// Mitsubishi GX Works2 project: optexfa-cdx_ce_v100a_j   PLC: Q04UDV

PROGRAM MAIN
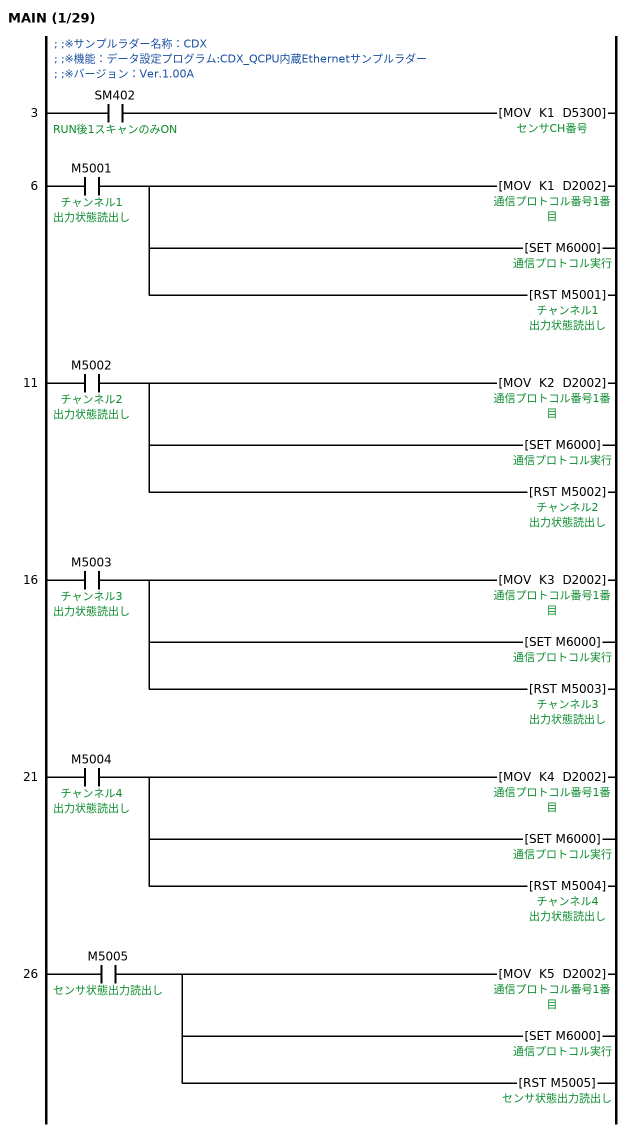
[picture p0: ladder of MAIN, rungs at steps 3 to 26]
; ※サンプルラダー名称：CDX
; ※機能：データ設定プログラム:CDX_QCPU内蔵Ethernetサンプルラダー
; ※バージョン：Ver.1.00A
3     LD      SM402  ; RUN後1スキャンのみON
      MOV     K1 D5300  ; センサCH番号
6     LD      M5001  ; チャンネル1 出力状態読出し
      MOV     K1 D2002  ; 通信プロトコル番号1番目
      SET     M6000  ; 通信プロトコル実行
      RST     M5001  ; チャンネル1 出力状態読出し
11    LD      M5002  ; チャンネル2 出力状態読出し
      MOV     K2 D2002
      SET     M6000  ; 通信プロトコル実行
      RST     M5002  ; チャンネル2 出力状態読出し
16    LD      M5003  ; チャンネル3 出力状態読出し
      MOV     K3 D2002
      SET     M6000  ; 通信プロトコル実行
      RST     M5003  ; チャンネル3 出力状態読出し
21    LD      M5004  ; チャンネル4 出力状態読出し
      MOV     K4 D2002
      SET     M6000  ; 通信プロトコル実行
      RST     M5004  ; チャンネル4 出力状態読出し
26    LD      M5005  ; センサ状態出力読出し
      MOV     K5 D2002
      SET     M6000  ; 通信プロトコル実行
      RST     M5005  ; センサ状態出力読出し
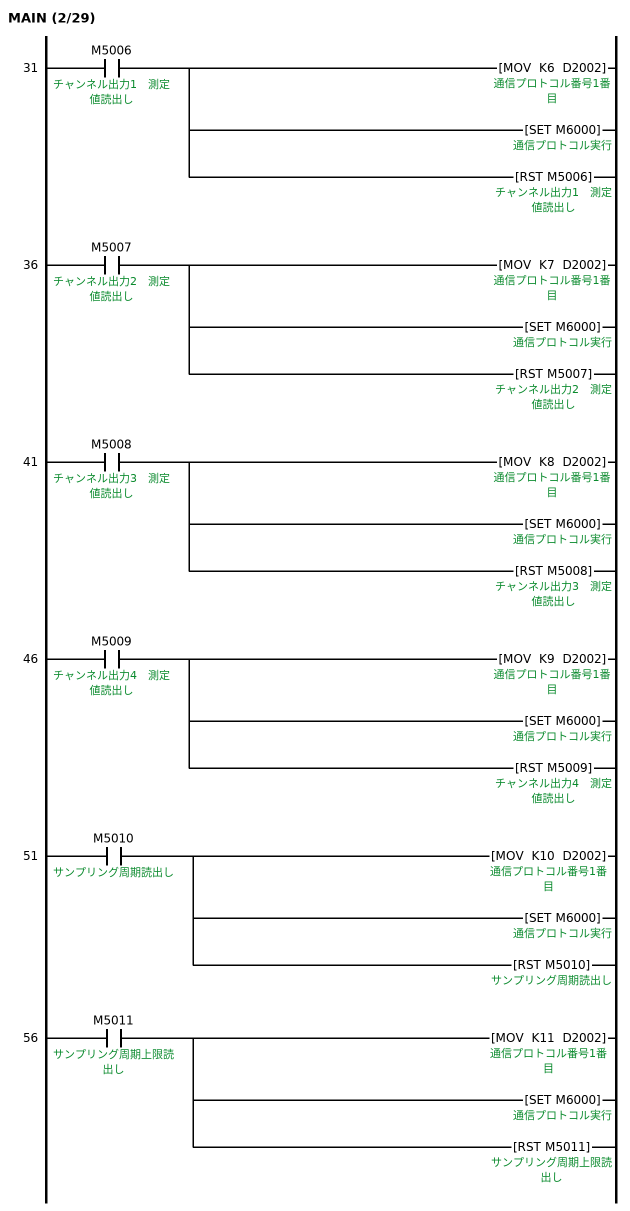
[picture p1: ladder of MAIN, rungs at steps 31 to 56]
31    LD      M5006  ; チャンネル出力1　測定値読出し
      MOV     K6 D2002
      SET     M6000  ; 通信プロトコル実行
      RST     M5006  ; チャンネル出力1　測定値読出し
36    LD      M5007  ; チャンネル出力2　測定値読出し
      MOV     K7 D2002
      SET     M6000  ; 通信プロトコル実行
      RST     M5007  ; チャンネル出力2　測定値読出し
41    LD      M5008  ; チャンネル出力3　測定値読出し
      MOV     K8 D2002
      SET     M6000  ; 通信プロトコル実行
      RST     M5008  ; チャンネル出力3　測定値読出し
46    LD      M5009  ; チャンネル出力4　測定値読出し
      MOV     K9 D2002
      SET     M6000  ; 通信プロトコル実行
      RST     M5009  ; チャンネル出力4　測定値読出し
51    LD      M5010  ; サンプリング周期読出し
      MOV     K10 D2002
      SET     M6000  ; 通信プロトコル実行
      RST     M5010  ; サンプリング周期読出し
56    LD      M5011  ; サンプリング周期上限読出し
      MOV     K11 D2002
      SET     M6000  ; 通信プロトコル実行
      RST     M5011  ; サンプリング周期上限読出し
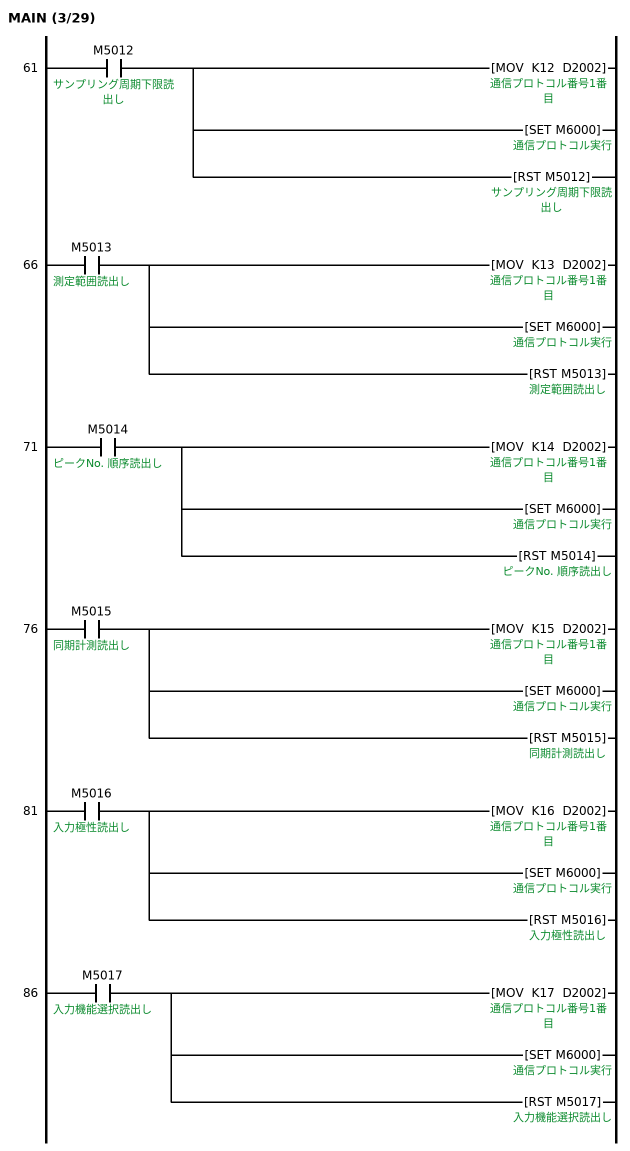
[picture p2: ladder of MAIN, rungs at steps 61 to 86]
61    LD      M5012  ; サンプリング周期下限読出し
      MOV     K12 D2002
      SET     M6000  ; 通信プロトコル実行
      RST     M5012  ; サンプリング周期下限読出し
66    LD      M5013  ; 測定範囲読出し
      MOV     K13 D2002
      SET     M6000  ; 通信プロトコル実行
      RST     M5013  ; 測定範囲読出し
71    LD      M5014  ; ピークNo. 順序読出し
      MOV     K14 D2002
      SET     M6000  ; 通信プロトコル実行
      RST     M5014  ; ピークNo. 順序読出し
76    LD      M5015  ; 同期計測読出し
      MOV     K15 D2002
      SET     M6000  ; 通信プロトコル実行
      RST     M5015  ; 同期計測読出し
81    LD      M5016  ; 入力極性読出し
      MOV     K16 D2002
      SET     M6000  ; 通信プロトコル実行
      RST     M5016  ; 入力極性読出し
86    LD      M5017  ; 入力機能選択読出し
      MOV     K17 D2002
      SET     M6000  ; 通信プロトコル実行
      RST     M5017  ; 入力機能選択読出し
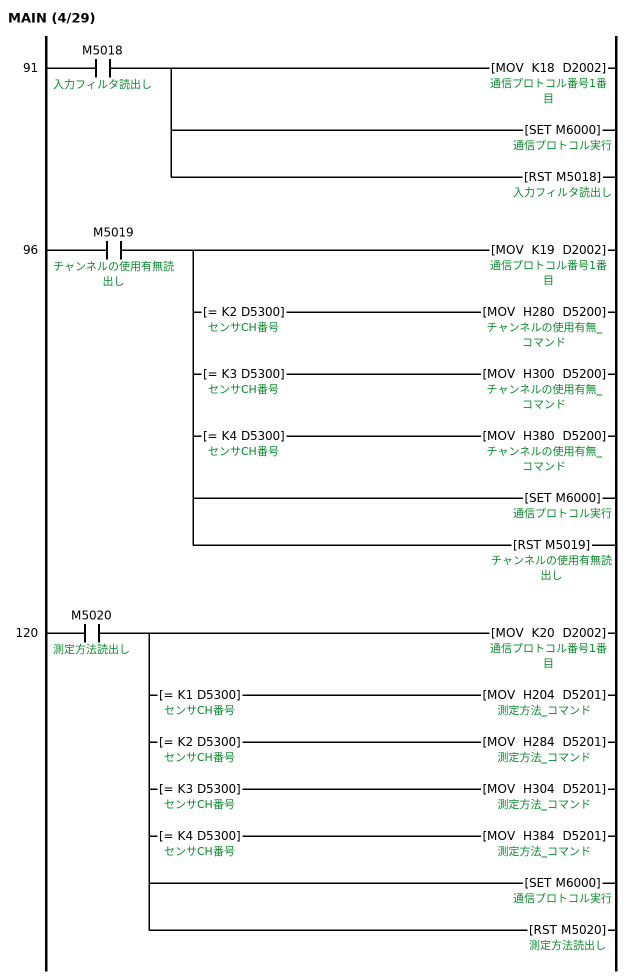
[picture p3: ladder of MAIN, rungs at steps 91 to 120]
91    LD      M5018  ; 入力フィルタ読出し
      MOV     K18 D2002
      SET     M6000  ; 通信プロトコル実行
      RST     M5018  ; 入力フィルタ読出し
96    LD      M5019  ; チャンネルの使用有無読出し
      MOV     K19 D2002
      MPS
      AND=    K2 D5300  ; センサCH番号
      MOV     H280 D5200  ; チャンネルの使用有無_コマンド
      MRD
      AND=    K3 D5300  ; センサCH番号
      MOV     H300 D5200
      MRD
      AND=    K4 D5300  ; センサCH番号
      MOV     H380 D5200
      MPP
      SET     M6000  ; 通信プロトコル実行
      RST     M5019  ; チャンネルの使用有無読出し
120   LD      M5020  ; 測定方法読出し
      MOV     K20 D2002
      MPS
      AND=    K1 D5300  ; センサCH番号
      MOV     H204 D5201  ; 測定方法_コマンド
      MRD
      AND=    K2 D5300  ; センサCH番号
      MOV     H284 D5201
      MRD
      AND=    K3 D5300  ; センサCH番号
      MOV     H304 D5201
      MRD
      AND=    K4 D5300  ; センサCH番号
      MOV     H384 D5201
      MPP
      SET     M6000  ; 通信プロトコル実行
      RST     M5020  ; 測定方法読出し
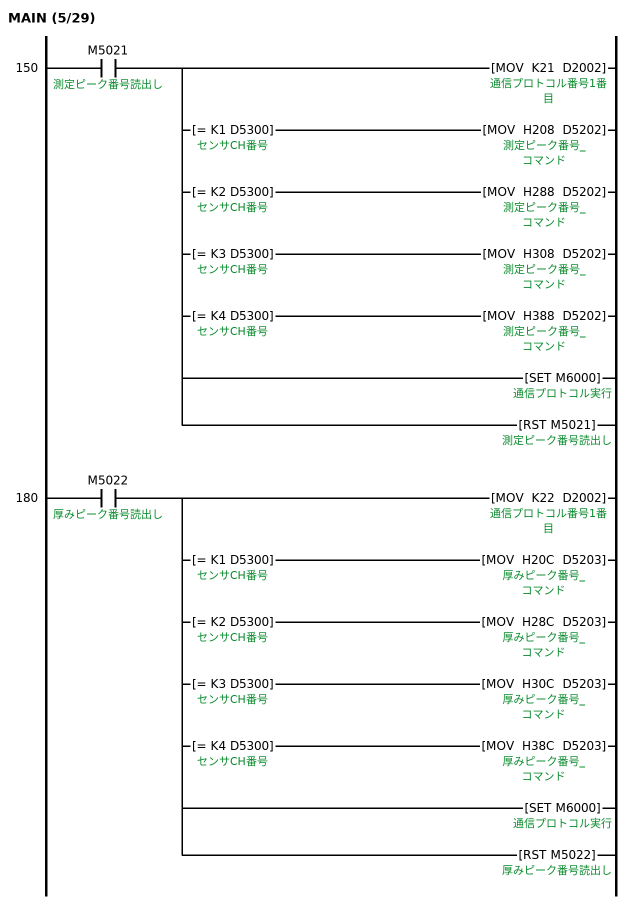
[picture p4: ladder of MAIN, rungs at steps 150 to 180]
150   LD      M5021  ; 測定ピーク番号読出し
      MOV     K21 D2002
      MPS
      AND=    K1 D5300  ; センサCH番号
      MOV     H208 D5202  ; 測定ピーク番号_コマンド
      MRD
      AND=    K2 D5300  ; センサCH番号
      MOV     H288 D5202
      MRD
      AND=    K3 D5300  ; センサCH番号
      MOV     H308 D5202
      MRD
      AND=    K4 D5300  ; センサCH番号
      MOV     H388 D5202
      MPP
      SET     M6000  ; 通信プロトコル実行
      RST     M5021  ; 測定ピーク番号読出し
180   LD      M5022  ; 厚みピーク番号読出し
      MOV     K22 D2002
      MPS
      AND=    K1 D5300  ; センサCH番号
      MOV     H20C D5203  ; 厚みピーク番号_コマンド
      MRD
      AND=    K2 D5300  ; センサCH番号
      MOV     H28C D5203
      MRD
      AND=    K3 D5300  ; センサCH番号
      MOV     H30C D5203
      MRD
      AND=    K4 D5300  ; センサCH番号
      MOV     H38C D5203
      MPP
      SET     M6000  ; 通信プロトコル実行
      RST     M5022  ; 厚みピーク番号読出し
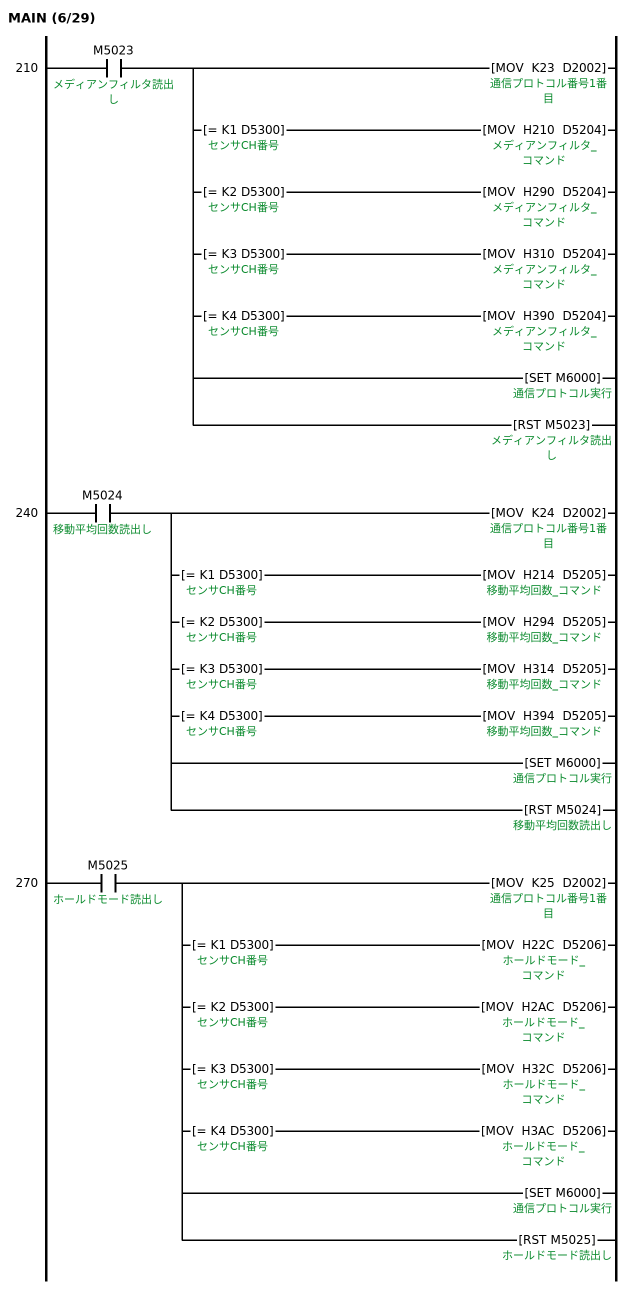
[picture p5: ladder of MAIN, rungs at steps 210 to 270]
210   LD      M5023  ; メディアンフィルタ読出し
      MOV     K23 D2002
      MPS
      AND=    K1 D5300  ; センサCH番号
      MOV     H210 D5204  ; メディアンフィルタ_コマンド
      MRD
      AND=    K2 D5300  ; センサCH番号
      MOV     H290 D5204
      MRD
      AND=    K3 D5300  ; センサCH番号
      MOV     H310 D5204
      MRD
      AND=    K4 D5300  ; センサCH番号
      MOV     H390 D5204
      MPP
      SET     M6000  ; 通信プロトコル実行
      RST     M5023  ; メディアンフィルタ読出し
240   LD      M5024  ; 移動平均回数読出し
      MOV     K24 D2002
      MPS
      AND=    K1 D5300  ; センサCH番号
      MOV     H214 D5205  ; 移動平均回数_コマンド
      MRD
      AND=    K2 D5300  ; センサCH番号
      MOV     H294 D5205
      MRD
      AND=    K3 D5300  ; センサCH番号
      MOV     H314 D5205
      MRD
      AND=    K4 D5300  ; センサCH番号
      MOV     H394 D5205
      MPP
      SET     M6000  ; 通信プロトコル実行
      RST     M5024  ; 移動平均回数読出し
270   LD      M5025  ; ホールドモード読出し
      MOV     K25 D2002
      MPS
      AND=    K1 D5300  ; センサCH番号
      MOV     H22C D5206  ; ホールドモード_コマンド
      MRD
      AND=    K2 D5300  ; センサCH番号
      MOV     H2AC D5206
      MRD
      AND=    K3 D5300  ; センサCH番号
      MOV     H32C D5206
      MRD
      AND=    K4 D5300  ; センサCH番号
      MOV     H3AC D5206
      MPP
      SET     M6000  ; 通信プロトコル実行
      RST     M5025  ; ホールドモード読出し
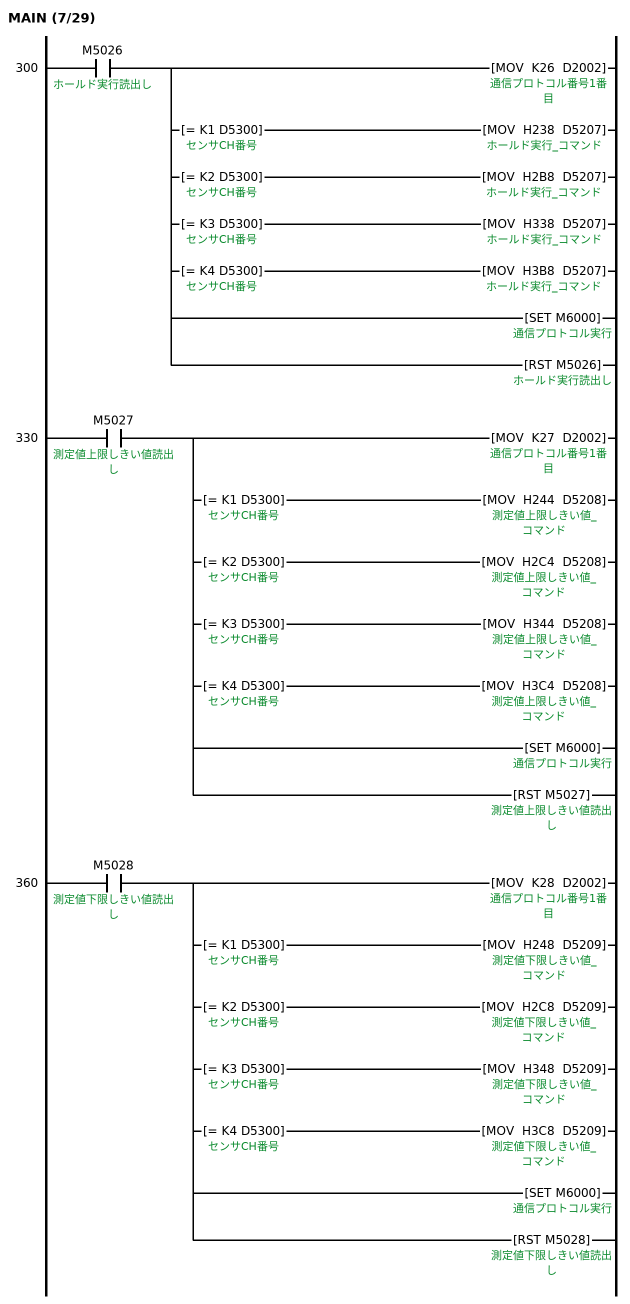
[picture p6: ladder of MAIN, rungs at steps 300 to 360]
300   LD      M5026  ; ホールド実行読出し
      MOV     K26 D2002
      MPS
      AND=    K1 D5300  ; センサCH番号
      MOV     H238 D5207  ; ホールド実行_コマンド
      MRD
      AND=    K2 D5300  ; センサCH番号
      MOV     H2B8 D5207
      MRD
      AND=    K3 D5300  ; センサCH番号
      MOV     H338 D5207
      MRD
      AND=    K4 D5300  ; センサCH番号
      MOV     H3B8 D5207
      MPP
      SET     M6000  ; 通信プロトコル実行
      RST     M5026  ; ホールド実行読出し
330   LD      M5027  ; 測定値上限しきい値読出し
      MOV     K27 D2002
      MPS
      AND=    K1 D5300  ; センサCH番号
      MOV     H244 D5208  ; 測定値上限しきい値_コマンド
      MRD
      AND=    K2 D5300  ; センサCH番号
      MOV     H2C4 D5208
      MRD
      AND=    K3 D5300  ; センサCH番号
      MOV     H344 D5208
      MRD
      AND=    K4 D5300  ; センサCH番号
      MOV     H3C4 D5208
      MPP
      SET     M6000  ; 通信プロトコル実行
      RST     M5027  ; 測定値上限しきい値読出し
360   LD      M5028  ; 測定値下限しきい値読出し
      MOV     K28 D2002
      MPS
      AND=    K1 D5300  ; センサCH番号
      MOV     H248 D5209  ; 測定値下限しきい値_コマンド
      MRD
      AND=    K2 D5300  ; センサCH番号
      MOV     H2C8 D5209
      MRD
      AND=    K3 D5300  ; センサCH番号
      MOV     H348 D5209
      MRD
      AND=    K4 D5300  ; センサCH番号
      MOV     H3C8 D5209
      MPP
      SET     M6000  ; 通信プロトコル実行
      RST     M5028  ; 測定値下限しきい値読出し
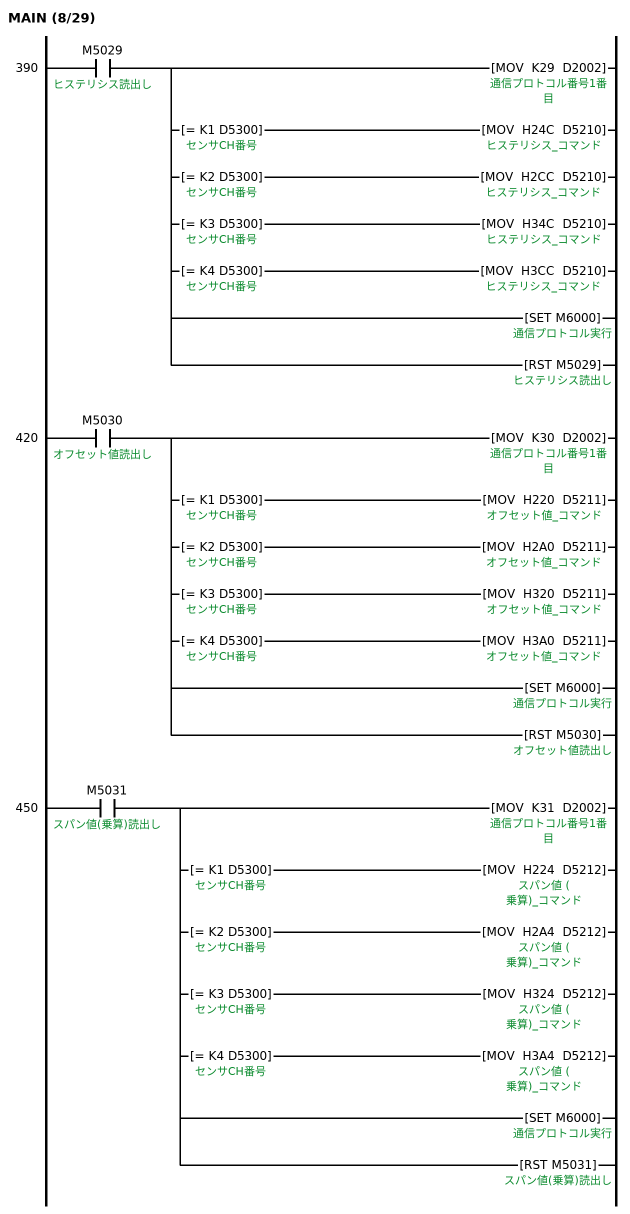
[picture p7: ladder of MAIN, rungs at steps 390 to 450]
390   LD      M5029  ; ヒステリシス読出し
      MOV     K29 D2002
      MPS
      AND=    K1 D5300  ; センサCH番号
      MOV     H24C D5210  ; ヒステリシス_コマンド
      MRD
      AND=    K2 D5300  ; センサCH番号
      MOV     H2CC D5210
      MRD
      AND=    K3 D5300  ; センサCH番号
      MOV     H34C D5210
      MRD
      AND=    K4 D5300  ; センサCH番号
      MOV     H3CC D5210
      MPP
      SET     M6000  ; 通信プロトコル実行
      RST     M5029  ; ヒステリシス読出し
420   LD      M5030  ; オフセット値読出し
      MOV     K30 D2002
      MPS
      AND=    K1 D5300  ; センサCH番号
      MOV     H220 D5211  ; オフセット値_コマンド
      MRD
      AND=    K2 D5300  ; センサCH番号
      MOV     H2A0 D5211
      MRD
      AND=    K3 D5300  ; センサCH番号
      MOV     H320 D5211
      MRD
      AND=    K4 D5300  ; センサCH番号
      MOV     H3A0 D5211
      MPP
      SET     M6000  ; 通信プロトコル実行
      RST     M5030  ; オフセット値読出し
450   LD      M5031  ; スパン値(乗算)読出し
      MOV     K31 D2002
      MPS
      AND=    K1 D5300  ; センサCH番号
      MOV     H224 D5212  ; スパン値 ( 乗算)_コマンド
      MRD
      AND=    K2 D5300  ; センサCH番号
      MOV     H2A4 D5212
      MRD
      AND=    K3 D5300  ; センサCH番号
      MOV     H324 D5212
      MRD
      AND=    K4 D5300  ; センサCH番号
      MOV     H3A4 D5212
      MPP
      SET     M6000  ; 通信プロトコル実行
      RST     M5031  ; スパン値(乗算)読出し
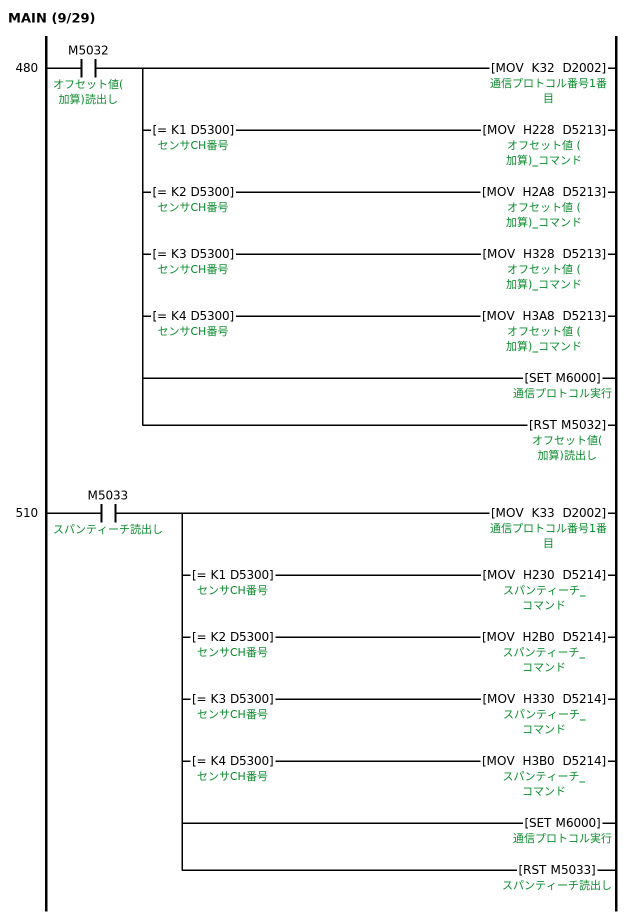
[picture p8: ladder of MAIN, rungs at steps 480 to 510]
480   LD      M5032  ; オフセット値(加算)読出し
      MOV     K32 D2002
      MPS
      AND=    K1 D5300  ; センサCH番号
      MOV     H228 D5213  ; オフセット値 ( 加算)_コマンド
      MRD
      AND=    K2 D5300  ; センサCH番号
      MOV     H2A8 D5213
      MRD
      AND=    K3 D5300  ; センサCH番号
      MOV     H328 D5213
      MRD
      AND=    K4 D5300  ; センサCH番号
      MOV     H3A8 D5213
      MPP
      SET     M6000  ; 通信プロトコル実行
      RST     M5032  ; オフセット値(加算)読出し
510   LD      M5033  ; スパンティーチ読出し
      MOV     K33 D2002
      MPS
      AND=    K1 D5300  ; センサCH番号
      MOV     H230 D5214  ; スパンティーチ_コマンド
      MRD
      AND=    K2 D5300  ; センサCH番号
      MOV     H2B0 D5214
      MRD
      AND=    K3 D5300  ; センサCH番号
      MOV     H330 D5214
      MRD
      AND=    K4 D5300  ; センサCH番号
      MOV     H3B0 D5214
      MPP
      SET     M6000  ; 通信プロトコル実行
      RST     M5033  ; スパンティーチ読出し
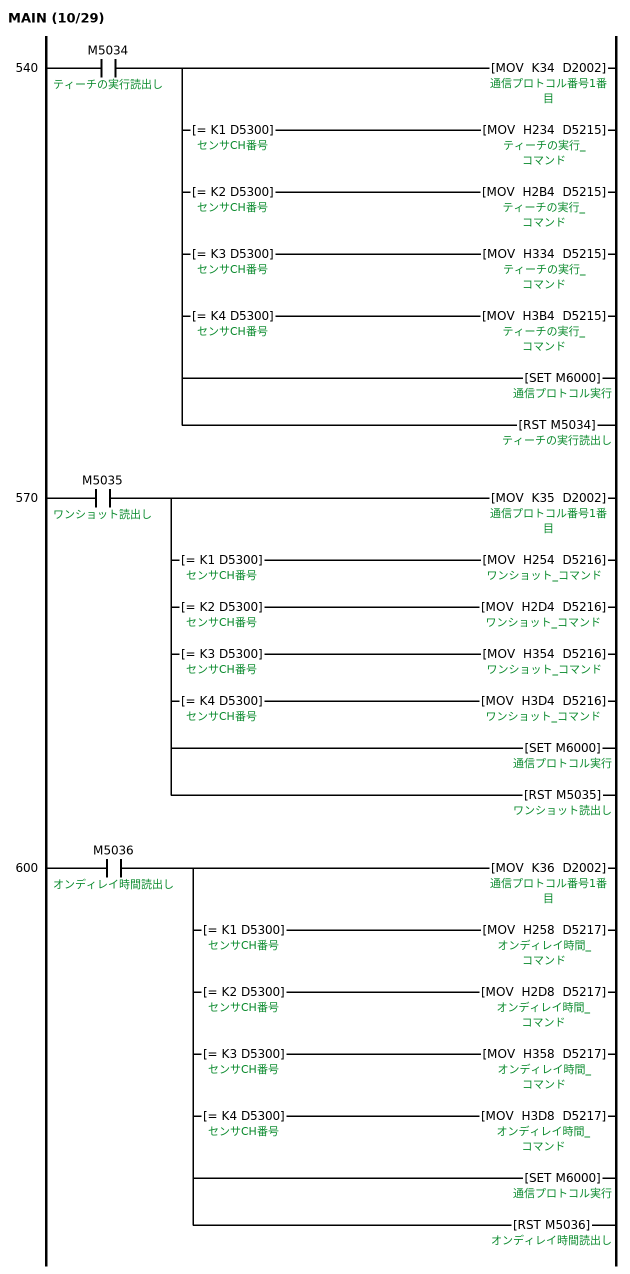
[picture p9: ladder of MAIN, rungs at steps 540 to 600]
540   LD      M5034  ; ティーチの実行読出し
      MOV     K34 D2002
      MPS
      AND=    K1 D5300  ; センサCH番号
      MOV     H234 D5215  ; ティーチの実行_コマンド
      MRD
      AND=    K2 D5300  ; センサCH番号
      MOV     H2B4 D5215
      MRD
      AND=    K3 D5300  ; センサCH番号
      MOV     H334 D5215
      MRD
      AND=    K4 D5300  ; センサCH番号
      MOV     H3B4 D5215
      MPP
      SET     M6000  ; 通信プロトコル実行
      RST     M5034  ; ティーチの実行読出し
570   LD      M5035  ; ワンショット読出し
      MOV     K35 D2002
      MPS
      AND=    K1 D5300  ; センサCH番号
      MOV     H254 D5216  ; ワンショット_コマンド
      MRD
      AND=    K2 D5300  ; センサCH番号
      MOV     H2D4 D5216
      MRD
      AND=    K3 D5300  ; センサCH番号
      MOV     H354 D5216
      MRD
      AND=    K4 D5300  ; センサCH番号
      MOV     H3D4 D5216
      MPP
      SET     M6000  ; 通信プロトコル実行
      RST     M5035  ; ワンショット読出し
600   LD      M5036  ; オンディレイ時間読出し
      MOV     K36 D2002
      MPS
      AND=    K1 D5300  ; センサCH番号
      MOV     H258 D5217  ; オンディレイ時間_コマンド
      MRD
      AND=    K2 D5300  ; センサCH番号
      MOV     H2D8 D5217
      MRD
      AND=    K3 D5300  ; センサCH番号
      MOV     H358 D5217
      MRD
      AND=    K4 D5300  ; センサCH番号
      MOV     H3D8 D5217
      MPP
      SET     M6000  ; 通信プロトコル実行
      RST     M5036  ; オンディレイ時間読出し
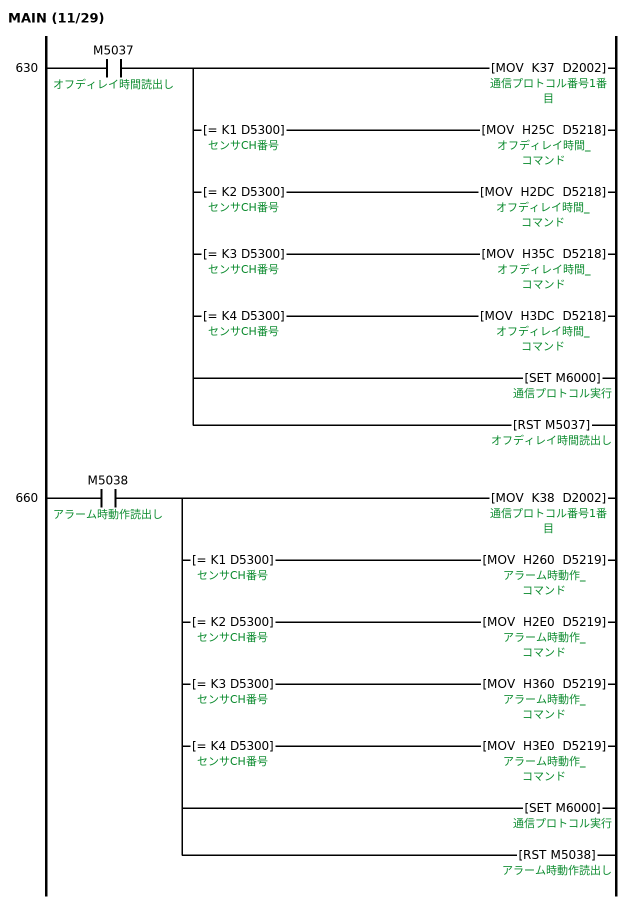
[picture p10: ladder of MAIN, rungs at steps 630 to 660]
630   LD      M5037  ; オフディレイ時間読出し
      MOV     K37 D2002
      MPS
      AND=    K1 D5300  ; センサCH番号
      MOV     H25C D5218  ; オフディレイ時間_コマンド
      MRD
      AND=    K2 D5300  ; センサCH番号
      MOV     H2DC D5218
      MRD
      AND=    K3 D5300  ; センサCH番号
      MOV     H35C D5218
      MRD
      AND=    K4 D5300  ; センサCH番号
      MOV     H3DC D5218
      MPP
      SET     M6000  ; 通信プロトコル実行
      RST     M5037  ; オフディレイ時間読出し
660   LD      M5038  ; アラーム時動作読出し
      MOV     K38 D2002
      MPS
      AND=    K1 D5300  ; センサCH番号
      MOV     H260 D5219  ; アラーム時動作_コマンド
      MRD
      AND=    K2 D5300  ; センサCH番号
      MOV     H2E0 D5219
      MRD
      AND=    K3 D5300  ; センサCH番号
      MOV     H360 D5219
      MRD
      AND=    K4 D5300  ; センサCH番号
      MOV     H3E0 D5219
      MPP
      SET     M6000  ; 通信プロトコル実行
      RST     M5038  ; アラーム時動作読出し
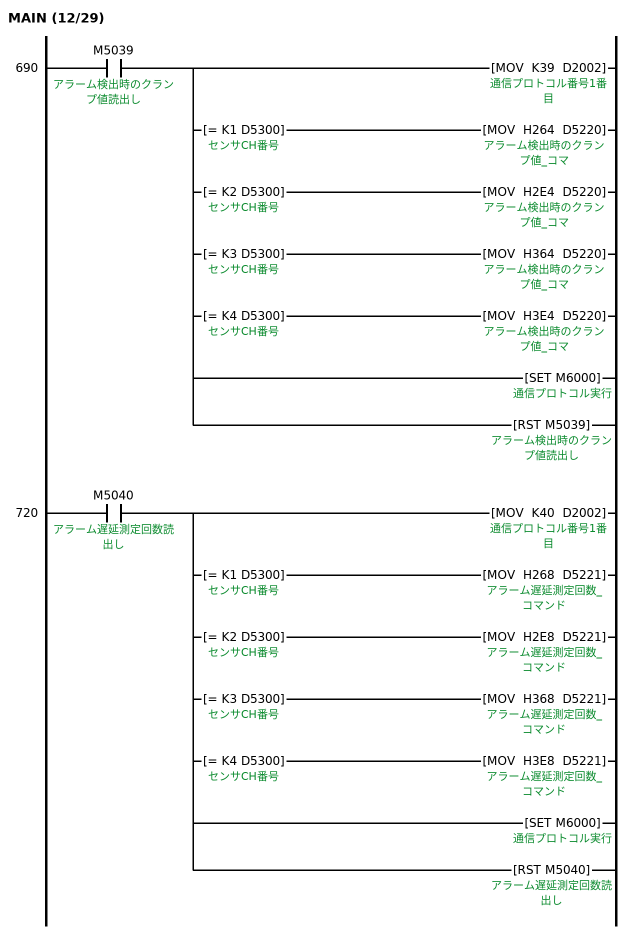
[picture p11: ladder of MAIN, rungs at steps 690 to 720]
690   LD      M5039  ; アラーム検出時のクランプ値読出し
      MOV     K39 D2002
      MPS
      AND=    K1 D5300  ; センサCH番号
      MOV     H264 D5220  ; アラーム検出時のクランプ値_コマ
      MRD
      AND=    K2 D5300  ; センサCH番号
      MOV     H2E4 D5220
      MRD
      AND=    K3 D5300  ; センサCH番号
      MOV     H364 D5220
      MRD
      AND=    K4 D5300  ; センサCH番号
      MOV     H3E4 D5220
      MPP
      SET     M6000  ; 通信プロトコル実行
      RST     M5039  ; アラーム検出時のクランプ値読出し
720   LD      M5040  ; アラーム遅延測定回数読出し
      MOV     K40 D2002
      MPS
      AND=    K1 D5300  ; センサCH番号
      MOV     H268 D5221  ; アラーム遅延測定回数_コマンド
      MRD
      AND=    K2 D5300  ; センサCH番号
      MOV     H2E8 D5221
      MRD
      AND=    K3 D5300  ; センサCH番号
      MOV     H368 D5221
      MRD
      AND=    K4 D5300  ; センサCH番号
      MOV     H3E8 D5221
      MPP
      SET     M6000  ; 通信プロトコル実行
      RST     M5040  ; アラーム遅延測定回数読出し
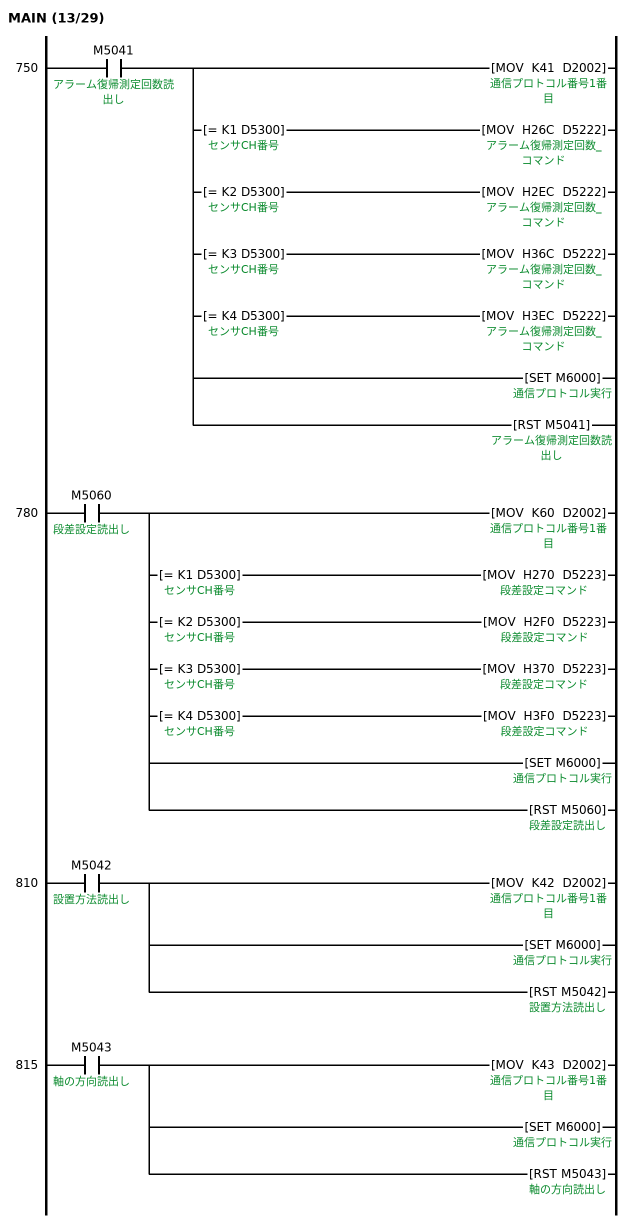
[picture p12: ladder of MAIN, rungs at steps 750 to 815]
750   LD      M5041  ; アラーム復帰測定回数読出し
      MOV     K41 D2002
      MPS
      AND=    K1 D5300  ; センサCH番号
      MOV     H26C D5222  ; アラーム復帰測定回数_コマンド
      MRD
      AND=    K2 D5300  ; センサCH番号
      MOV     H2EC D5222
      MRD
      AND=    K3 D5300  ; センサCH番号
      MOV     H36C D5222
      MRD
      AND=    K4 D5300  ; センサCH番号
      MOV     H3EC D5222
      MPP
      SET     M6000  ; 通信プロトコル実行
      RST     M5041  ; アラーム復帰測定回数読出し
780   LD      M5060  ; 段差設定読出し
      MOV     K60 D2002
      MPS
      AND=    K1 D5300  ; センサCH番号
      MOV     H270 D5223  ; 段差設定コマンド
      MRD
      AND=    K2 D5300  ; センサCH番号
      MOV     H2F0 D5223
      MRD
      AND=    K3 D5300  ; センサCH番号
      MOV     H370 D5223
      MRD
      AND=    K4 D5300  ; センサCH番号
      MOV     H3F0 D5223
      MPP
      SET     M6000  ; 通信プロトコル実行
      RST     M5060  ; 段差設定読出し
810   LD      M5042  ; 設置方法読出し
      MOV     K42 D2002
      SET     M6000  ; 通信プロトコル実行
      RST     M5042  ; 設置方法読出し
815   LD      M5043  ; 軸の方向読出し
      MOV     K43 D2002
      SET     M6000  ; 通信プロトコル実行
      RST     M5043  ; 軸の方向読出し
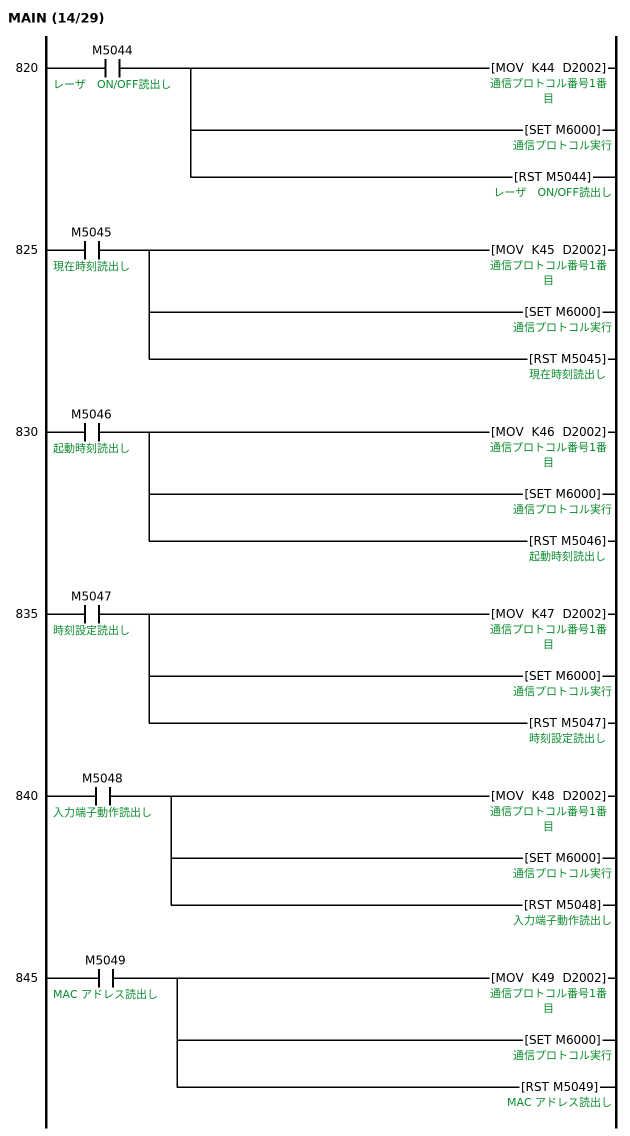
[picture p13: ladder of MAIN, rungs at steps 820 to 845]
820   LD      M5044  ; レーザ　ON/OFF読出し
      MOV     K44 D2002
      SET     M6000  ; 通信プロトコル実行
      RST     M5044  ; レーザ　ON/OFF読出し
825   LD      M5045  ; 現在時刻読出し
      MOV     K45 D2002
      SET     M6000  ; 通信プロトコル実行
      RST     M5045  ; 現在時刻読出し
830   LD      M5046  ; 起動時刻読出し
      MOV     K46 D2002
      SET     M6000  ; 通信プロトコル実行
      RST     M5046  ; 起動時刻読出し
835   LD      M5047  ; 時刻設定読出し
      MOV     K47 D2002
      SET     M6000  ; 通信プロトコル実行
      RST     M5047  ; 時刻設定読出し
840   LD      M5048  ; 入力端子動作読出し
      MOV     K48 D2002
      SET     M6000  ; 通信プロトコル実行
      RST     M5048  ; 入力端子動作読出し
845   LD      M5049  ; MAC アドレス読出し
      MOV     K49 D2002
      SET     M6000  ; 通信プロトコル実行
      RST     M5049  ; MAC アドレス読出し
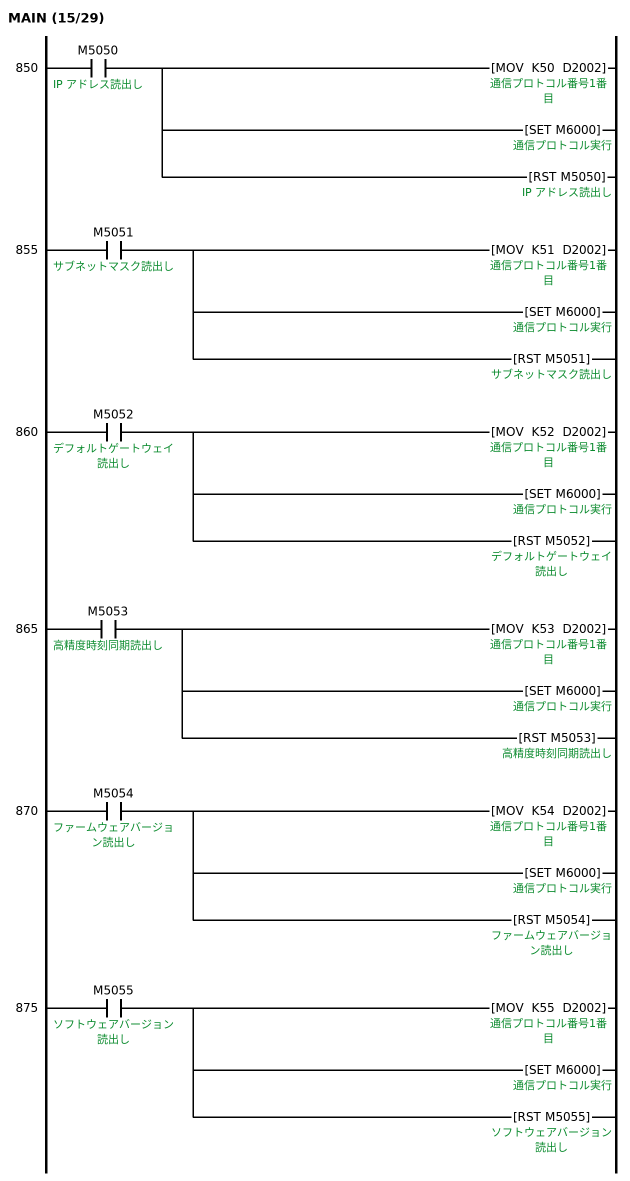
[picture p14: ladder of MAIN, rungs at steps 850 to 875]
850   LD      M5050  ; IP アドレス読出し
      MOV     K50 D2002
      SET     M6000  ; 通信プロトコル実行
      RST     M5050  ; IP アドレス読出し
855   LD      M5051  ; サブネットマスク読出し
      MOV     K51 D2002
      SET     M6000  ; 通信プロトコル実行
      RST     M5051  ; サブネットマスク読出し
860   LD      M5052  ; デフォルトゲートウェイ読出し
      MOV     K52 D2002
      SET     M6000  ; 通信プロトコル実行
      RST     M5052  ; デフォルトゲートウェイ読出し
865   LD      M5053  ; 高精度時刻同期読出し
      MOV     K53 D2002
      SET     M6000  ; 通信プロトコル実行
      RST     M5053  ; 高精度時刻同期読出し
870   LD      M5054  ; ファームウェアバージョン読出し
      MOV     K54 D2002
      SET     M6000  ; 通信プロトコル実行
      RST     M5054  ; ファームウェアバージョン読出し
875   LD      M5055  ; ソフトウェアバージョン読出し
      MOV     K55 D2002
      SET     M6000  ; 通信プロトコル実行
      RST     M5055  ; ソフトウェアバージョン読出し
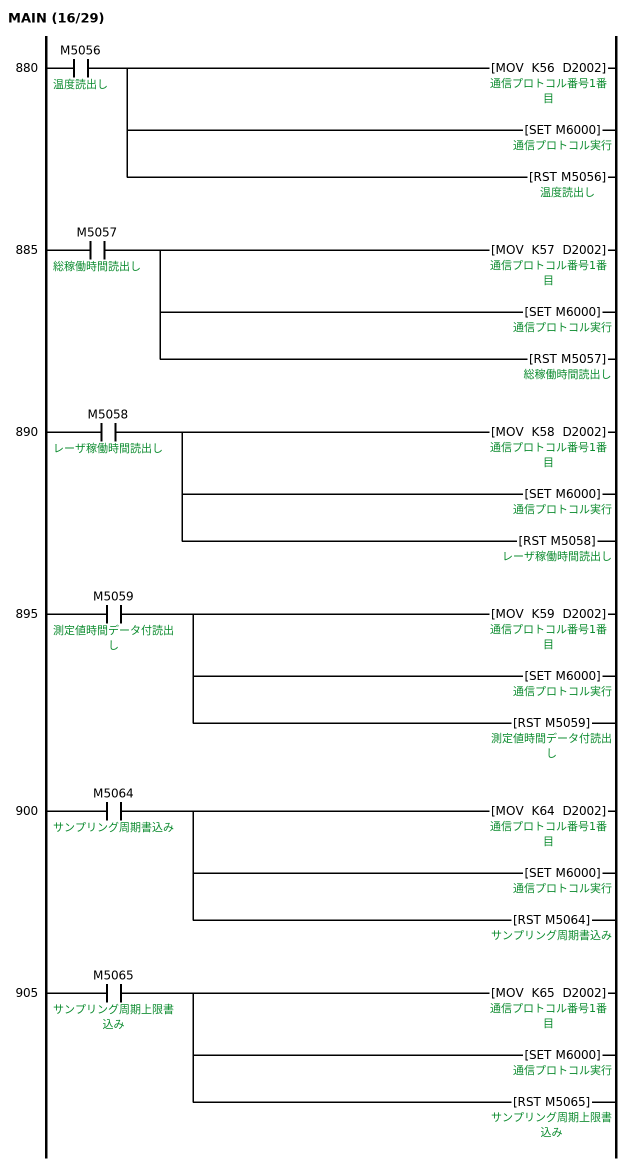
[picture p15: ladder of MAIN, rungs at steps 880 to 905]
880   LD      M5056  ; 温度読出し
      MOV     K56 D2002
      SET     M6000  ; 通信プロトコル実行
      RST     M5056  ; 温度読出し
885   LD      M5057  ; 総稼働時間読出し
      MOV     K57 D2002
      SET     M6000  ; 通信プロトコル実行
      RST     M5057  ; 総稼働時間読出し
890   LD      M5058  ; レーザ稼働時間読出し
      MOV     K58 D2002
      SET     M6000  ; 通信プロトコル実行
      RST     M5058  ; レーザ稼働時間読出し
895   LD      M5059  ; 測定値時間データ付読出し
      MOV     K59 D2002
      SET     M6000  ; 通信プロトコル実行
      RST     M5059  ; 測定値時間データ付読出し
900   LD      M5064  ; サンプリング周期書込み
      MOV     K64 D2002
      SET     M6000  ; 通信プロトコル実行
      RST     M5064  ; サンプリング周期書込み
905   LD      M5065  ; サンプリング周期上限書込み
      MOV     K65 D2002
      SET     M6000  ; 通信プロトコル実行
      RST     M5065  ; サンプリング周期上限書込み
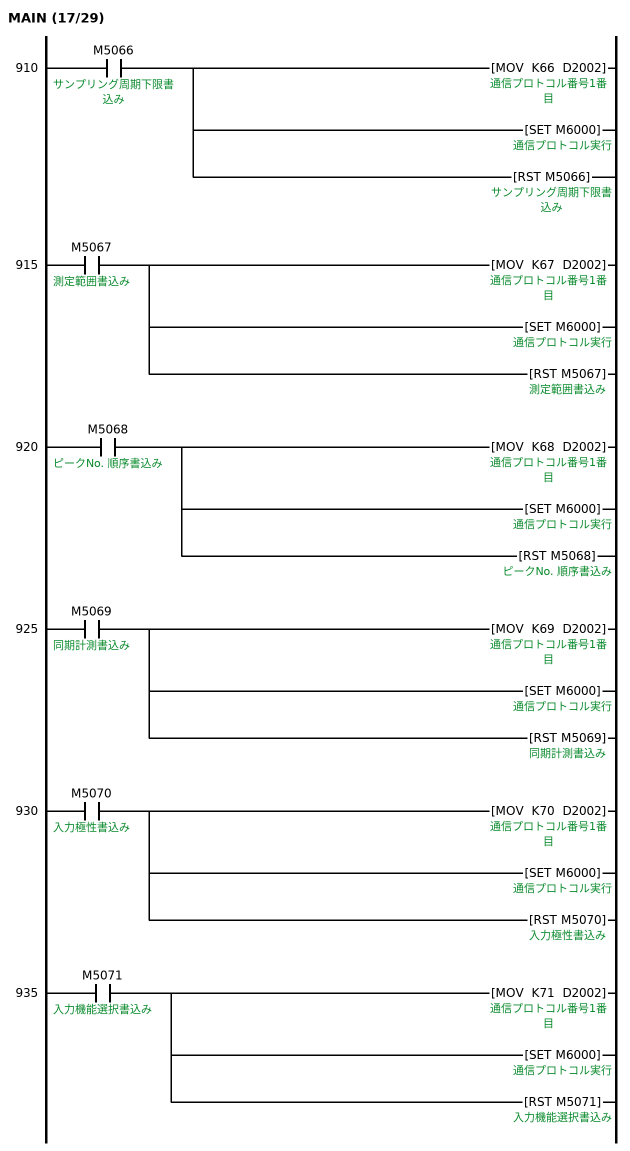
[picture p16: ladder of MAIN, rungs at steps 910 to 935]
910   LD      M5066  ; サンプリング周期下限書込み
      MOV     K66 D2002
      SET     M6000  ; 通信プロトコル実行
      RST     M5066  ; サンプリング周期下限書込み
915   LD      M5067  ; 測定範囲書込み
      MOV     K67 D2002
      SET     M6000  ; 通信プロトコル実行
      RST     M5067  ; 測定範囲書込み
920   LD      M5068  ; ピークNo. 順序書込み
      MOV     K68 D2002
      SET     M6000  ; 通信プロトコル実行
      RST     M5068  ; ピークNo. 順序書込み
925   LD      M5069  ; 同期計測書込み
      MOV     K69 D2002
      SET     M6000  ; 通信プロトコル実行
      RST     M5069  ; 同期計測書込み
930   LD      M5070  ; 入力極性書込み
      MOV     K70 D2002
      SET     M6000  ; 通信プロトコル実行
      RST     M5070  ; 入力極性書込み
935   LD      M5071  ; 入力機能選択書込み
      MOV     K71 D2002
      SET     M6000  ; 通信プロトコル実行
      RST     M5071  ; 入力機能選択書込み
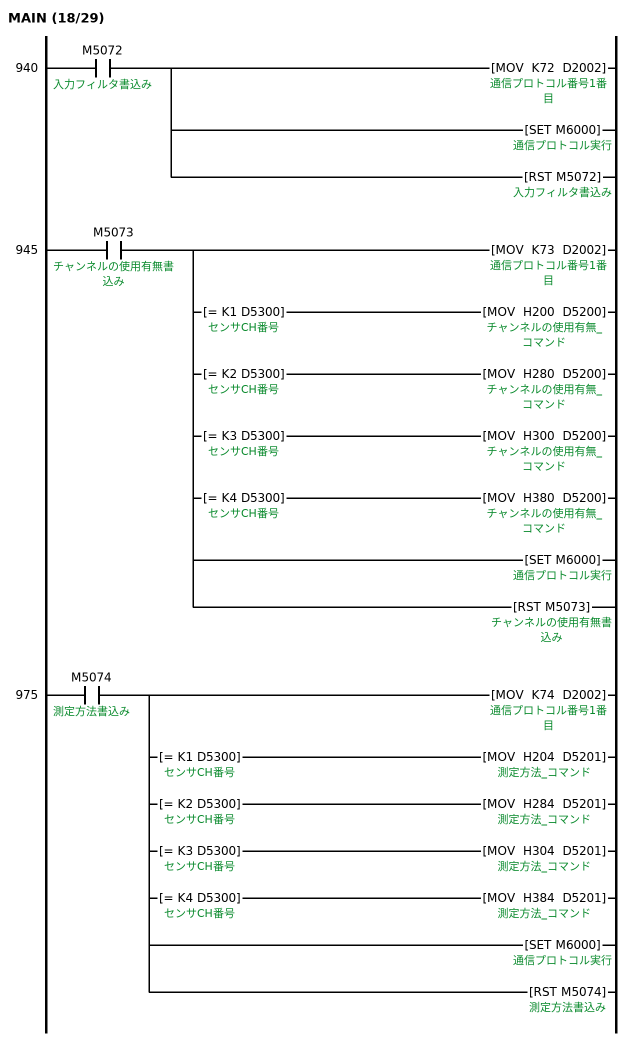
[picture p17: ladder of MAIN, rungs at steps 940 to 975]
940   LD      M5072  ; 入力フィルタ書込み
      MOV     K72 D2002
      SET     M6000  ; 通信プロトコル実行
      RST     M5072  ; 入力フィルタ書込み
945   LD      M5073  ; チャンネルの使用有無書込み
      MOV     K73 D2002
      MPS
      AND=    K1 D5300  ; センサCH番号
      MOV     H200 D5200
      MRD
      AND=    K2 D5300  ; センサCH番号
      MOV     H280 D5200
      MRD
      AND=    K3 D5300  ; センサCH番号
      MOV     H300 D5200
      MRD
      AND=    K4 D5300  ; センサCH番号
      MOV     H380 D5200
      MPP
      SET     M6000  ; 通信プロトコル実行
      RST     M5073  ; チャンネルの使用有無書込み
975   LD      M5074  ; 測定方法書込み
      MOV     K74 D2002
      MPS
      AND=    K1 D5300  ; センサCH番号
      MOV     H204 D5201
      MRD
      AND=    K2 D5300  ; センサCH番号
      MOV     H284 D5201
      MRD
      AND=    K3 D5300  ; センサCH番号
      MOV     H304 D5201
      MRD
      AND=    K4 D5300  ; センサCH番号
      MOV     H384 D5201
      MPP
      SET     M6000  ; 通信プロトコル実行
      RST     M5074  ; 測定方法書込み
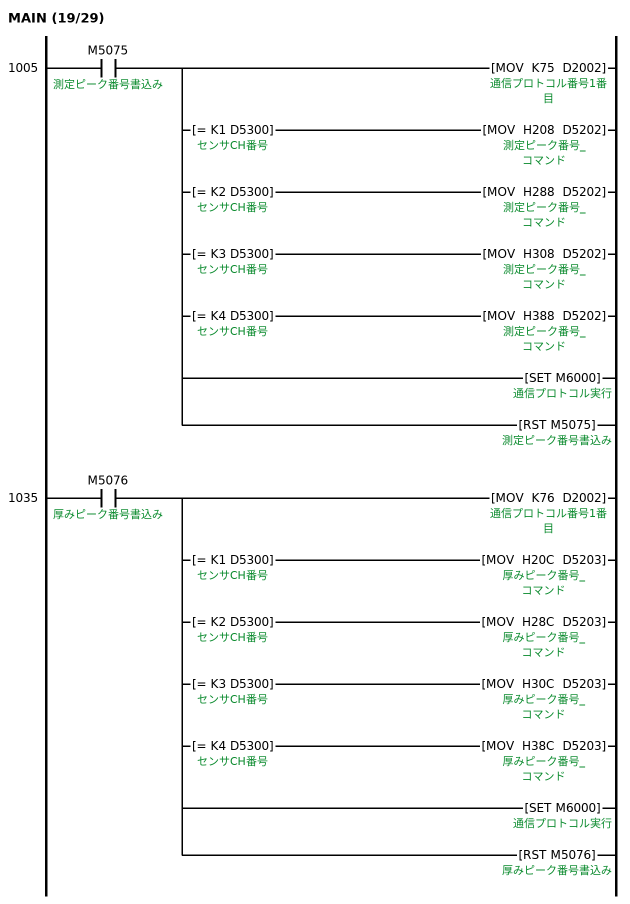
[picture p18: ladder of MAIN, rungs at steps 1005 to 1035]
1005  LD      M5075  ; 測定ピーク番号書込み
      MOV     K75 D2002
      MPS
      AND=    K1 D5300  ; センサCH番号
      MOV     H208 D5202
      MRD
      AND=    K2 D5300  ; センサCH番号
      MOV     H288 D5202
      MRD
      AND=    K3 D5300  ; センサCH番号
      MOV     H308 D5202
      MRD
      AND=    K4 D5300  ; センサCH番号
      MOV     H388 D5202
      MPP
      SET     M6000  ; 通信プロトコル実行
      RST     M5075  ; 測定ピーク番号書込み
1035  LD      M5076  ; 厚みピーク番号書込み
      MOV     K76 D2002
      MPS
      AND=    K1 D5300  ; センサCH番号
      MOV     H20C D5203
      MRD
      AND=    K2 D5300  ; センサCH番号
      MOV     H28C D5203
      MRD
      AND=    K3 D5300  ; センサCH番号
      MOV     H30C D5203
      MRD
      AND=    K4 D5300  ; センサCH番号
      MOV     H38C D5203
      MPP
      SET     M6000  ; 通信プロトコル実行
      RST     M5076  ; 厚みピーク番号書込み
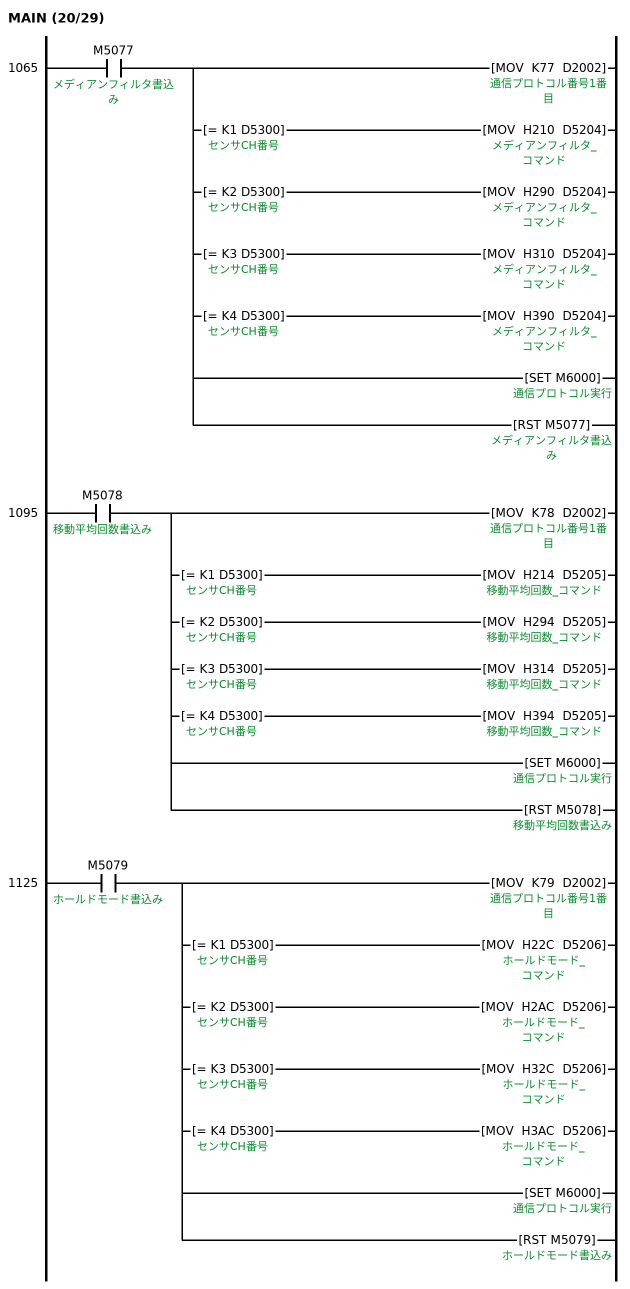
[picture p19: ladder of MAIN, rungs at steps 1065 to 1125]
1065  LD      M5077  ; メディアンフィルタ書込み
      MOV     K77 D2002
      MPS
      AND=    K1 D5300  ; センサCH番号
      MOV     H210 D5204
      MRD
      AND=    K2 D5300  ; センサCH番号
      MOV     H290 D5204
      MRD
      AND=    K3 D5300  ; センサCH番号
      MOV     H310 D5204
      MRD
      AND=    K4 D5300  ; センサCH番号
      MOV     H390 D5204
      MPP
      SET     M6000  ; 通信プロトコル実行
      RST     M5077  ; メディアンフィルタ書込み
1095  LD      M5078  ; 移動平均回数書込み
      MOV     K78 D2002
      MPS
      AND=    K1 D5300  ; センサCH番号
      MOV     H214 D5205
      MRD
      AND=    K2 D5300  ; センサCH番号
      MOV     H294 D5205
      MRD
      AND=    K3 D5300  ; センサCH番号
      MOV     H314 D5205
      MRD
      AND=    K4 D5300  ; センサCH番号
      MOV     H394 D5205
      MPP
      SET     M6000  ; 通信プロトコル実行
      RST     M5078  ; 移動平均回数書込み
1125  LD      M5079  ; ホールドモード書込み
      MOV     K79 D2002
      MPS
      AND=    K1 D5300  ; センサCH番号
      MOV     H22C D5206
      MRD
      AND=    K2 D5300  ; センサCH番号
      MOV     H2AC D5206
      MRD
      AND=    K3 D5300  ; センサCH番号
      MOV     H32C D5206
      MRD
      AND=    K4 D5300  ; センサCH番号
      MOV     H3AC D5206
      MPP
      SET     M6000  ; 通信プロトコル実行
      RST     M5079  ; ホールドモード書込み
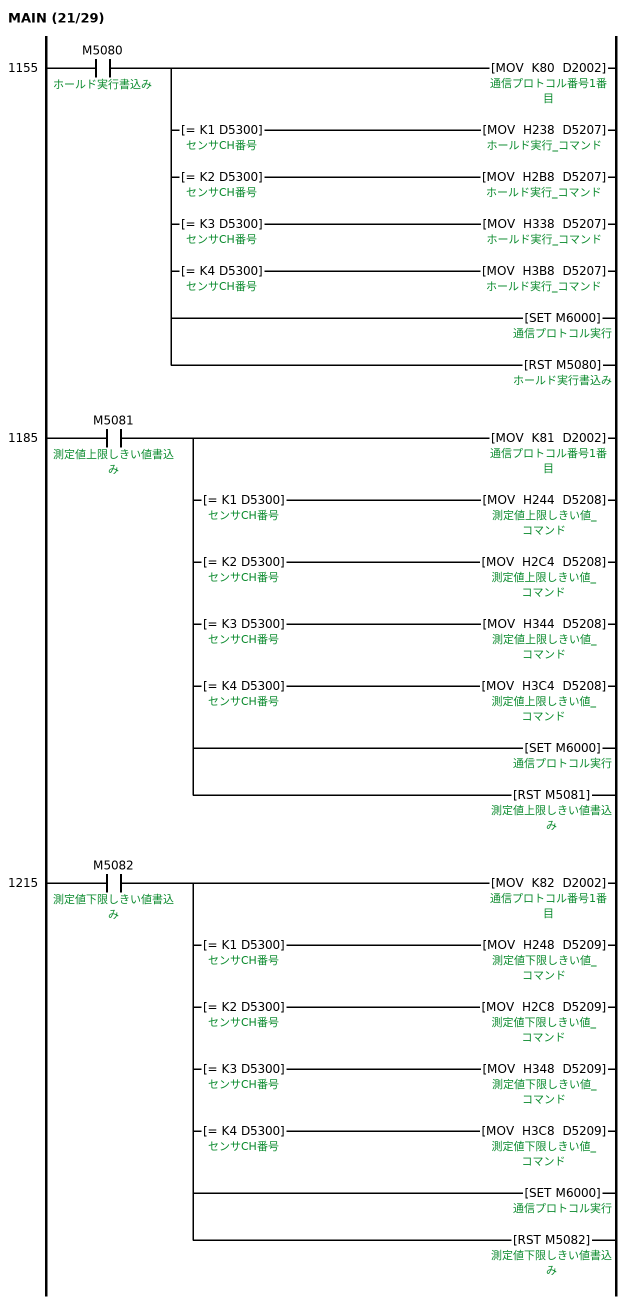
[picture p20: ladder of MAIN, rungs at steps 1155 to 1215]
1155  LD      M5080  ; ホールド実行書込み
      MOV     K80 D2002
      MPS
      AND=    K1 D5300  ; センサCH番号
      MOV     H238 D5207
      MRD
      AND=    K2 D5300  ; センサCH番号
      MOV     H2B8 D5207
      MRD
      AND=    K3 D5300  ; センサCH番号
      MOV     H338 D5207
      MRD
      AND=    K4 D5300  ; センサCH番号
      MOV     H3B8 D5207
      MPP
      SET     M6000  ; 通信プロトコル実行
      RST     M5080  ; ホールド実行書込み
1185  LD      M5081  ; 測定値上限しきい値書込み
      MOV     K81 D2002
      MPS
      AND=    K1 D5300  ; センサCH番号
      MOV     H244 D5208
      MRD
      AND=    K2 D5300  ; センサCH番号
      MOV     H2C4 D5208
      MRD
      AND=    K3 D5300  ; センサCH番号
      MOV     H344 D5208
      MRD
      AND=    K4 D5300  ; センサCH番号
      MOV     H3C4 D5208
      MPP
      SET     M6000  ; 通信プロトコル実行
      RST     M5081  ; 測定値上限しきい値書込み
1215  LD      M5082  ; 測定値下限しきい値書込み
      MOV     K82 D2002
      MPS
      AND=    K1 D5300  ; センサCH番号
      MOV     H248 D5209
      MRD
      AND=    K2 D5300  ; センサCH番号
      MOV     H2C8 D5209
      MRD
      AND=    K3 D5300  ; センサCH番号
      MOV     H348 D5209
      MRD
      AND=    K4 D5300  ; センサCH番号
      MOV     H3C8 D5209
      MPP
      SET     M6000  ; 通信プロトコル実行
      RST     M5082  ; 測定値下限しきい値書込み
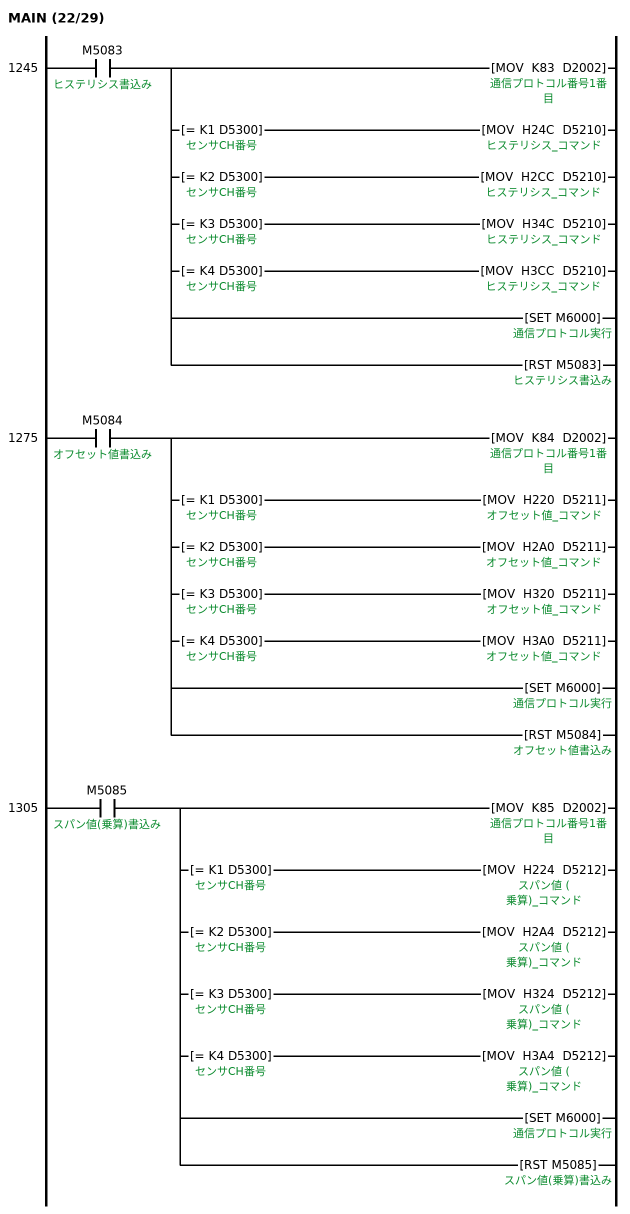
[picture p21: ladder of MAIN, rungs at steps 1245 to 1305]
1245  LD      M5083  ; ヒステリシス書込み
      MOV     K83 D2002
      MPS
      AND=    K1 D5300  ; センサCH番号
      MOV     H24C D5210
      MRD
      AND=    K2 D5300  ; センサCH番号
      MOV     H2CC D5210
      MRD
      AND=    K3 D5300  ; センサCH番号
      MOV     H34C D5210
      MRD
      AND=    K4 D5300  ; センサCH番号
      MOV     H3CC D5210
      MPP
      SET     M6000  ; 通信プロトコル実行
      RST     M5083  ; ヒステリシス書込み
1275  LD      M5084  ; オフセット値書込み
      MOV     K84 D2002
      MPS
      AND=    K1 D5300  ; センサCH番号
      MOV     H220 D5211
      MRD
      AND=    K2 D5300  ; センサCH番号
      MOV     H2A0 D5211
      MRD
      AND=    K3 D5300  ; センサCH番号
      MOV     H320 D5211
      MRD
      AND=    K4 D5300  ; センサCH番号
      MOV     H3A0 D5211
      MPP
      SET     M6000  ; 通信プロトコル実行
      RST     M5084  ; オフセット値書込み
1305  LD      M5085  ; スパン値(乗算)書込み
      MOV     K85 D2002
      MPS
      AND=    K1 D5300  ; センサCH番号
      MOV     H224 D5212
      MRD
      AND=    K2 D5300  ; センサCH番号
      MOV     H2A4 D5212
      MRD
      AND=    K3 D5300  ; センサCH番号
      MOV     H324 D5212
      MRD
      AND=    K4 D5300  ; センサCH番号
      MOV     H3A4 D5212
      MPP
      SET     M6000  ; 通信プロトコル実行
      RST     M5085  ; スパン値(乗算)書込み
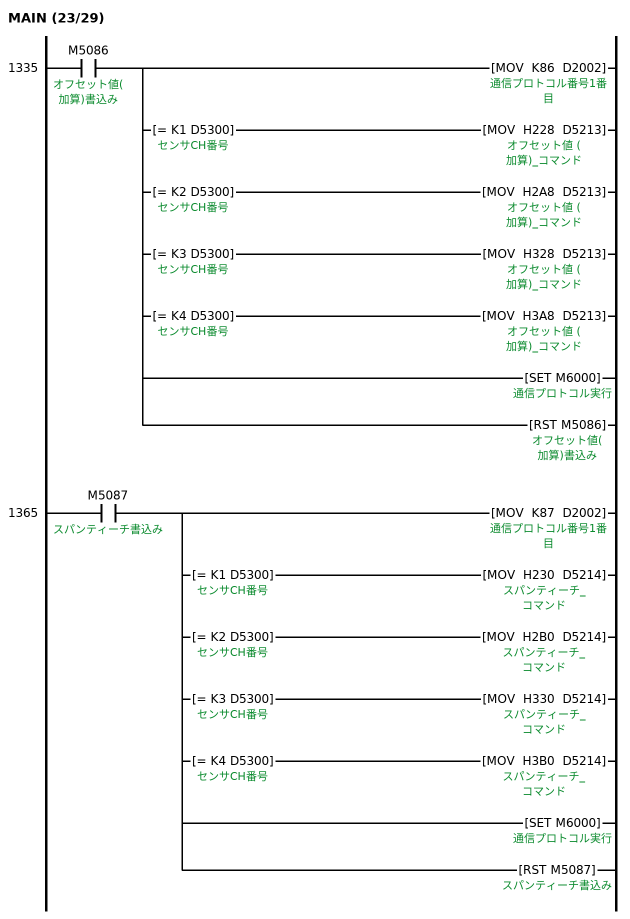
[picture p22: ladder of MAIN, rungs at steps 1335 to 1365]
1335  LD      M5086  ; オフセット値(加算)書込み
      MOV     K86 D2002
      MPS
      AND=    K1 D5300  ; センサCH番号
      MOV     H228 D5213
      MRD
      AND=    K2 D5300  ; センサCH番号
      MOV     H2A8 D5213
      MRD
      AND=    K3 D5300  ; センサCH番号
      MOV     H328 D5213
      MRD
      AND=    K4 D5300  ; センサCH番号
      MOV     H3A8 D5213
      MPP
      SET     M6000  ; 通信プロトコル実行
      RST     M5086  ; オフセット値(加算)書込み
1365  LD      M5087  ; スパンティーチ書込み
      MOV     K87 D2002
      MPS
      AND=    K1 D5300  ; センサCH番号
      MOV     H230 D5214
      MRD
      AND=    K2 D5300  ; センサCH番号
      MOV     H2B0 D5214
      MRD
      AND=    K3 D5300  ; センサCH番号
      MOV     H330 D5214
      MRD
      AND=    K4 D5300  ; センサCH番号
      MOV     H3B0 D5214
      MPP
      SET     M6000  ; 通信プロトコル実行
      RST     M5087  ; スパンティーチ書込み
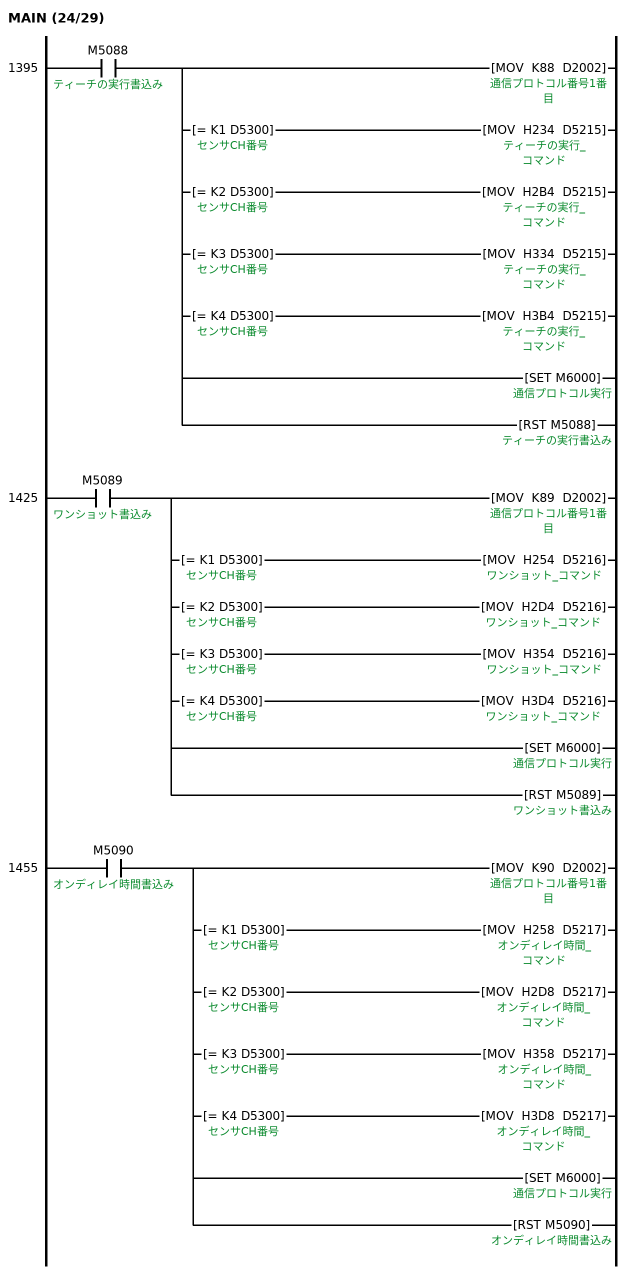
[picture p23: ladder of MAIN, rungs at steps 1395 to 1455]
1395  LD      M5088  ; ティーチの実行書込み
      MOV     K88 D2002
      MPS
      AND=    K1 D5300  ; センサCH番号
      MOV     H234 D5215
      MRD
      AND=    K2 D5300  ; センサCH番号
      MOV     H2B4 D5215
      MRD
      AND=    K3 D5300  ; センサCH番号
      MOV     H334 D5215
      MRD
      AND=    K4 D5300  ; センサCH番号
      MOV     H3B4 D5215
      MPP
      SET     M6000  ; 通信プロトコル実行
      RST     M5088  ; ティーチの実行書込み
1425  LD      M5089  ; ワンショット書込み
      MOV     K89 D2002
      MPS
      AND=    K1 D5300  ; センサCH番号
      MOV     H254 D5216
      MRD
      AND=    K2 D5300  ; センサCH番号
      MOV     H2D4 D5216
      MRD
      AND=    K3 D5300  ; センサCH番号
      MOV     H354 D5216
      MRD
      AND=    K4 D5300  ; センサCH番号
      MOV     H3D4 D5216
      MPP
      SET     M6000  ; 通信プロトコル実行
      RST     M5089  ; ワンショット書込み
1455  LD      M5090  ; オンディレイ時間書込み
      MOV     K90 D2002
      MPS
      AND=    K1 D5300  ; センサCH番号
      MOV     H258 D5217
      MRD
      AND=    K2 D5300  ; センサCH番号
      MOV     H2D8 D5217
      MRD
      AND=    K3 D5300  ; センサCH番号
      MOV     H358 D5217
      MRD
      AND=    K4 D5300  ; センサCH番号
      MOV     H3D8 D5217
      MPP
      SET     M6000  ; 通信プロトコル実行
      RST     M5090  ; オンディレイ時間書込み
1485  LD      M5091  ; オフディレイ時間書込み
      MOV     K91 D2002
      MPS
      AND=    K1 D5300  ; センサCH番号
      MOV     H25C D5218
      MRD
      AND=    K2 D5300  ; センサCH番号
      MOV     H2DC D5218
      MRD
      AND=    K3 D5300  ; センサCH番号
      MOV     H35C D5218
      MRD
      AND=    K4 D5300  ; センサCH番号
      MOV     H3DC D5218
      MPP
      SET     M6000  ; 通信プロトコル実行
      RST     M5091  ; オフディレイ時間書込み
1515  LD      M5092  ; アラーム時動作書込み
      MOV     K92 D2002
      MPS
      AND=    K1 D5300  ; センサCH番号
      MOV     H260 D5219
      MRD
      AND=    K2 D5300  ; センサCH番号
      MOV     H2E0 D5219
      MRD
      AND=    K3 D5300  ; センサCH番号
      MOV     H360 D5219
      MRD
      AND=    K4 D5300  ; センサCH番号
      MOV     H3E0 D5219
      MPP
      SET     M6000  ; 通信プロトコル実行
      RST     M5092  ; アラーム時動作書込み
1545  LD      M5093  ; アラーム検出時のクランプ値書込み
      MOV     K93 D2002
      MPS
      AND=    K1 D5300  ; センサCH番号
      MOV     H264 D5220
      MRD
      AND=    K2 D5300  ; センサCH番号
      MOV     H2E4 D5220
      MRD
      AND=    K3 D5300  ; センサCH番号
      MOV     H364 D5220
      MRD
      AND=    K4 D5300  ; センサCH番号
      MOV     H3E4 D5220
      MPP
      SET     M6000  ; 通信プロトコル実行
      RST     M5093  ; アラーム検出時のクランプ値書込み
1575  LD      M5094  ; アラーム遅延測定回数書込み
      MOV     K94 D2002
      MPS
      AND=    K1 D5300  ; センサCH番号
      MOV     H268 D5221
      MRD
      AND=    K2 D5300  ; センサCH番号
      MOV     H2E8 D5221
      MRD
      AND=    K3 D5300  ; センサCH番号
      MOV     H368 D5221
      MRD
      AND=    K4 D5300  ; センサCH番号
      MOV     H3E8 D5221
      MPP
      SET     M6000  ; 通信プロトコル実行
      RST     M5094  ; アラーム遅延測定回数書込み
1605  LD      M5095  ; アラーム復帰測定回数書込み
      MOV     K95 D2002
      MPS
      AND=    K1 D5300  ; センサCH番号
      MOV     H26C D5222
      MRD
      AND=    K2 D5300  ; センサCH番号
      MOV     H2EC D5222
      MRD
      AND=    K3 D5300  ; センサCH番号
      MOV     H36C D5222
      MRD
      AND=    K4 D5300  ; センサCH番号
      MOV     H3EC D5222
      MPP
      SET     M6000  ; 通信プロトコル実行
      RST     M5095  ; アラーム復帰測定回数書込み
1635  LD      M5107  ; 段差設定書込み
      MOV     K107 D2002
      MPS
      AND=    K1 D5300  ; センサCH番号
      MOV     H270 D5223
      MRD
      AND=    K2 D5300  ; センサCH番号
      MOV     H2F0 D5223
      MRD
      AND=    K3 D5300  ; センサCH番号
      MOV     H370 D5223
      MRD
      AND=    K4 D5300  ; センサCH番号
      MOV     H3F0 D5223
      MPP
      SET     M6000  ; 通信プロトコル実行
      RST     M5107  ; 段差設定書込み
1665  LD      M5096  ; 設置方法書込み
      MOV     K96 D2002
      SET     M6000  ; 通信プロトコル実行
      RST     M5096  ; 設置方法書込み
1670  LD      M5097  ; 軸の方向書込み
      MOV     K97 D2002
      SET     M6000  ; 通信プロトコル実行
      RST     M5097  ; 軸の方向書込み
1675  LD      M5098  ; レーザ　ON/OFF書込み
      MOV     K98 D2002
      SET     M6000  ; 通信プロトコル実行
      RST     M5098  ; レーザ　ON/OFF書込み
1680  LD      M5099  ; 時刻更新書込み
      MOV     K99 D2002
      SET     M6000  ; 通信プロトコル実行
      RST     M5099  ; 時刻更新書込み
1685  LD      M5100  ; 現在時刻更新書込み
      MOV     K100 D2002
      SET     M6000  ; 通信プロトコル実行
      RST     M5100  ; 現在時刻更新書込み
1690  LD      M5101  ; 初期化
      MOV     K101 D2002
      SET     M6000  ; 通信プロトコル実行
      RST     M5101  ; 初期化
1695  LD      M5102  ; 入力端子動作書込み
      MOV     K102 D2002
      SET     M6000  ; 通信プロトコル実行
      RST     M5102  ; 入力端子動作書込み
1700  LD      M5103  ; IP アドレス書込み
      MOV     K103 D2002
      SET     M6000  ; 通信プロトコル実行
      RST     M5103  ; IP アドレス書込み
1705  LD      M5104  ; サブネットマスク書込み
      MOV     K104 D2002
      SET     M6000  ; 通信プロトコル実行
      RST     M5104  ; サブネットマスク書込み
1710  LD      M5105  ; デフォルトゲートウェイ書込み
      MOV     K105 D2002
      SET     M6000  ; 通信プロトコル実行
      RST     M5105  ; デフォルトゲートウェイ書込み
1715  LD      SM1354  ; 内蔵Ethernet準備完了
      ANDP    M6000  ; 通信プロトコル実行
      SP.ECPRTCL "U1" K1 K1 D2000 M5501  ; 通信プロトコル実行結果 / 通信プロトコル完了
1733  LD      M5501  ; 通信プロトコル完了
      MPS
      ANI     M5502  ; 通信プロトコル異常
      SET     M6003  ; 通信プロトコル正常終了
      MRD
      AND     M5502  ; 通信プロトコル異常
      SET     M6004  ; 通信プロトコル異常終了
      MOVP    D2001 D2100  ; 通信プロトコル完了ステータス / 通信エラーコード格納
      MPP
      RST     M6000  ; 通信プロトコル実行
1745  END
END_PROGRAM

// device comments not shown above
M5106  ; 高精度時刻同期書込み
D2003  ; 通信プロトコル番号2番目
D2004  ; 通信プロトコル番号3番目
D2005  ; 通信プロトコル番号4番目
D2006  ; 通信プロトコル番号5番目
D2007  ; 通信プロトコル番号6番目
D2008  ; 通信プロトコル番号7番目
D2009  ; 通信プロトコル番号8番目
D3000  ; 通信プロトコル実行状態
D5000  ; チャンネル1 出力状態+0
D5001  ; チャンネル1 出力状態+1
D5002  ; チャンネル2 出力状態+0
D5003  ; チャンネル2 出力状態+1
D5004  ; チャンネル3 出力状態+0
D5005  ; チャンネル3 出力状態+1
D5006  ; チャンネル4 出力状態+0
D5007  ; チャンネル4 出力状態+1
D5008  ; センサ状態出力+0
D5009  ; センサ状態出力+1
D5010  ; チャンネル出力1　測定値+0
D5011  ; チャンネル出力1　測定値+1
D5012  ; チャンネル出力2　測定値+0
D5013  ; チャンネル出力2　測定値+1
D5014  ; チャンネル出力3　測定値+0
D5015  ; チャンネル出力3　測定値+1
D5016  ; チャンネル出力4　測定値+0
D5017  ; チャンネル出力4　測定値+1
D5018  ; サンプリング周期+0
D5019  ; サンプリング周期+1
D5020  ; サンプリング周期上限+0
D5021  ; サンプリング周期上限+1
D5022  ; サンプリング周期下限+0
D5023  ; サンプリング周期下限+1
D5024  ; 測定範囲+0
D5025  ; 測定範囲+1
D5026  ; ピークNo. 順序+0
D5027  ; ピークNo. 順序+1
D5028  ; 同期計測+0
D5029  ; 同期計測+1
D5030  ; 入力極性+0
D5031  ; 入力極性+1
D5032  ; 入力機能選択+0
D5033  ; 入力機能選択+1
D5034  ; 入力フィルタ+0
D5035  ; 入力フィルタ+1
D5036  ; チャンネルの使用有無+0
D5037  ; チャンネルの使用有無+1
D5038  ; 測定方法+0
D5039  ; 測定方法+1
D5040  ; 測定ピーク番号+0
D5041  ; 測定ピーク番号+1
D5042  ; 厚みピーク番号+0
D5043  ; 厚みピーク番号+1
D5044  ; メディアンフィルタ+0
D5045  ; メディアンフィルタ+1
D5046  ; 移動平均回数+0
D5047  ; 移動平均回数+1
D5048  ; ホールドモード+0
D5049  ; ホールドモード+1
D5050  ; ホールド実行+0
D5051  ; ホールド実行+1
D5052  ; 測定値上限しきい値+0
D5053  ; 測定値上限しきい値+1
D5054  ; 測定値下限しきい値+0
D5055  ; 測定値下限しきい値+1
D5056  ; ヒステリシス+0
D5057  ; ヒステリシス+1
D5058  ; オフセット値+0
D5059  ; オフセット値+1
D5060  ; スパン値 ( 乗算)+0
D5061  ; スパン値 ( 乗算)+1
D5062  ; オフセット値 (加算)+0
D5063  ; オフセット値 (加算)+1
D5064  ; スパンティーチ+0
D5065  ; スパンティーチ+1
D5066  ; ティーチの実行+0
D5067  ; ティーチの実行+1
D5068  ; ワンショット+0
D5069  ; ワンショット+1
D5070  ; オンディレイ時間+0
D5071  ; オンディレイ時間+1
D5072  ; オフディレイ時間+0
D5073  ; オフディレイ時間+1
D5074  ; アラーム時動作+0
D5075  ; アラーム時動作+1
D5076  ; アラーム検出時のクランプ値+0
D5077  ; アラーム検出時のクランプ値+1
D5078  ; アラーム遅延測定回数+0
D5079  ; アラーム遅延測定回数+1
D5080  ; アラーム復帰測定回数+0
D5081  ; アラーム復帰測定回数+1
D5082  ; 設置方法+0
D5083  ; 設置方法+1
D5084  ; 軸の方向+0
D5085  ; 軸の方向+1
D5086  ; レーザ　ON/OFF+0
D5087  ; レーザ　ON/OFF+1
D5088  ; 現在時刻+0
D5089  ; 現在時刻+1
D5090  ; 起動時刻+0
D5091  ; 起動時刻+1
D5092  ; 時刻設定+0
D5093  ; 時刻設定+1
D5098  ; 入力端子動作+0
D5099  ; 入力端子動作+1
D5100  ; MAC アドレス+0
D5101  ; MAC アドレス+1
D5102  ; IP アドレス+0
D5103  ; IP アドレス+1
D5104  ; サブネットマスク+0
D5105  ; サブネットマスク+1
D5106  ; デフォルトゲートウェイ+0
D5107  ; デフォルトゲートウェイ+1
D5108  ; 高精度時刻同期+0
D5109  ; 高精度時刻同期+1
D5110  ; ファームウェアバージョン+0
D5111  ; ファームウェアバージョン+1
D5112  ; ソフトウェアバージョン+0
D5113  ; ソフトウェアバージョン+1
D5114  ; 温度+0
D5115  ; 温度+1
D5116  ; 総稼働時間+0
D5117  ; 総稼働時間+1
D5118  ; レーザ稼働時間+0
D5119  ; レーザ稼働時間+1
D5120  ; 測定値時間データ付+0
D5121  ; 測定値時間データ付+1
D5122  ; 測定値時間データ付+2
D5123  ; 測定値時間データ付+3
D5124  ; 測定値時間データ付+4
D5125  ; 測定値時間データ付+5
D5126  ; 段差設定+0
D5127  ; 段差設定+1
